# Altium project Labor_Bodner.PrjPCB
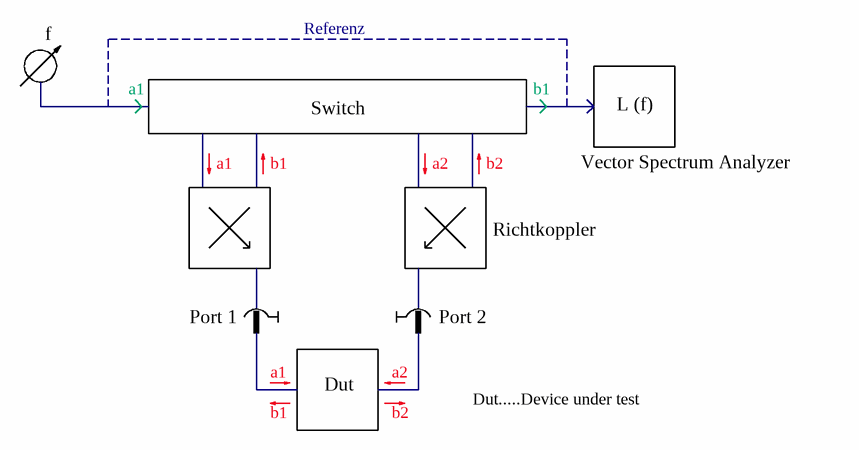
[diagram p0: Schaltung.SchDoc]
1 sheet, 0 parts. Net scope: global (net labels, ports and power ports of the same name join across sheets).

## Sheet Schaltung.SchDoc
size A4; PageSetup: Record=PageOptions¦CenterHorizontal=True¦CenterVertical=True¦PrintScale=0.97¦XCorrection=1.00¦YCorrection=1.00¦PrintKind=0¦BorderSize=5000000¦LeftOffset=0¦BottomOffset=0¦Orientation=2¦PaperLength=1000¦PaperWidth=1000¦Scale=100¦PaperSource=7¦PrintQuality=-4¦MediaType=1¦DitherType=10¦PaperKind=A4¦PrintScaleMode=1

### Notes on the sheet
- f
- Referenz
- a1
- Switch
- b1
- L (f)
- a2
- b2
- Vector Spectrum Analyzer
- Richtkoppler
- Port 1
- Port 2
- Dut
- Dut.....Device under test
